VERSION 5.7 ;
  NOWIREEXTENSIONATPIN ON ;
  DIVIDERCHAR "/" ;
  BUSBITCHARS "[]" ;
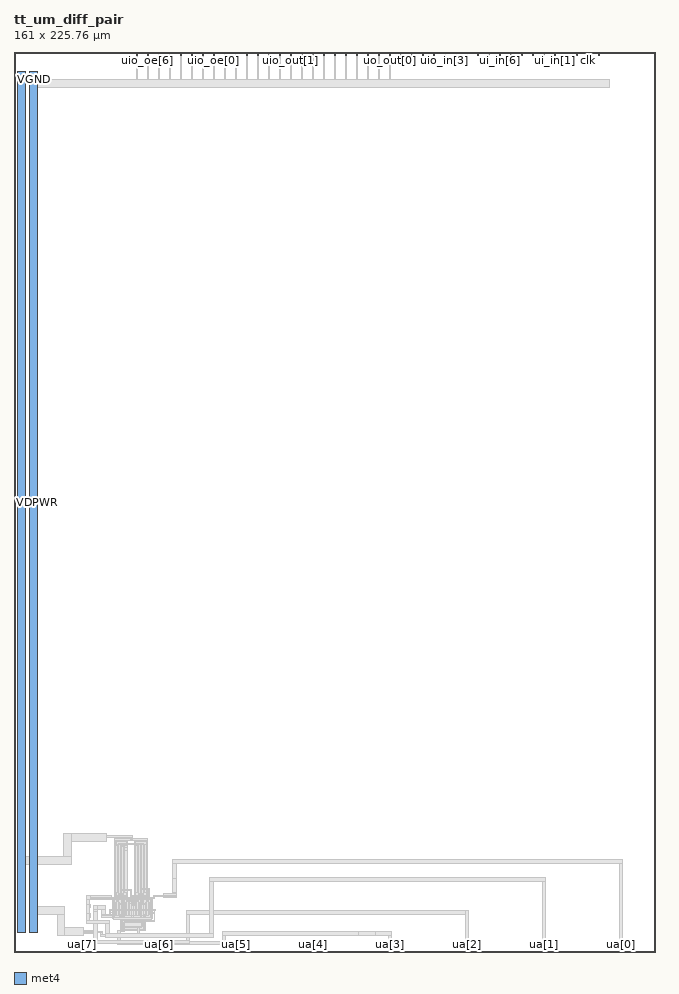
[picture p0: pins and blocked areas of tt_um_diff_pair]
MACRO tt_um_diff_pair
  CLASS BLOCK ;
  FOREIGN tt_um_diff_pair ;
  ORIGIN 0.000 0.000 ;
  SIZE 161.000 BY 225.760 ;
  PIN clk
    DIRECTION INPUT ;
    USE SIGNAL ;
    PORT
      LAYER met4 ;
        RECT 143.830 224.760 144.130 225.760 ;
    END
  END clk
  PIN ena
    DIRECTION INPUT ;
    USE SIGNAL ;
    PORT
      LAYER met4 ;
        RECT 146.590 224.760 146.890 225.760 ;
    END
  END ena
  PIN rst_n
    DIRECTION INPUT ;
    USE SIGNAL ;
    PORT
      LAYER met4 ;
        RECT 141.070 224.760 141.370 225.760 ;
    END
  END rst_n
  PIN ua[0]
    DIRECTION INOUT ;
    USE SIGNAL ;
    ANTENNADIFFAREA 5.220000 ;
    PORT
      LAYER met4 ;
        RECT 151.810 0.000 152.710 1.000 ;
    END
  END ua[0]
  PIN ua[1]
    DIRECTION INOUT ;
    USE SIGNAL ;
    ANTENNAGATEAREA 3.000000 ;
    PORT
      LAYER met4 ;
        RECT 132.490 0.000 133.390 1.000 ;
    END
  END ua[1]
  PIN ua[2]
    DIRECTION INOUT ;
    USE SIGNAL ;
    ANTENNAGATEAREA 3.000000 ;
    PORT
      LAYER met4 ;
        RECT 113.170 0.000 114.070 1.000 ;
    END
  END ua[2]
  PIN ua[3]
    DIRECTION INOUT ;
    USE SIGNAL ;
    ANTENNAGATEAREA 4.000000 ;
    PORT
      LAYER met4 ;
        RECT 93.850 0.000 94.750 1.000 ;
    END
  END ua[3]
  PIN ua[4]
    DIRECTION INOUT ;
    USE SIGNAL ;
    PORT
      LAYER met4 ;
        RECT 74.530 0.000 75.430 1.000 ;
    END
  END ua[4]
  PIN ua[5]
    DIRECTION INOUT ;
    USE SIGNAL ;
    PORT
      LAYER met4 ;
        RECT 55.210 0.000 56.110 1.000 ;
    END
  END ua[5]
  PIN ua[6]
    DIRECTION INOUT ;
    USE SIGNAL ;
    PORT
      LAYER met4 ;
        RECT 35.890 0.000 36.790 1.000 ;
    END
  END ua[6]
  PIN ua[7]
    DIRECTION INOUT ;
    USE SIGNAL ;
    PORT
      LAYER met4 ;
        RECT 16.570 0.000 17.470 1.000 ;
    END
  END ua[7]
  PIN ui_in[0]
    DIRECTION INPUT ;
    USE SIGNAL ;
    PORT
      LAYER met4 ;
        RECT 138.310 224.760 138.610 225.760 ;
    END
  END ui_in[0]
  PIN ui_in[1]
    DIRECTION INPUT ;
    USE SIGNAL ;
    PORT
      LAYER met4 ;
        RECT 135.550 224.760 135.850 225.760 ;
    END
  END ui_in[1]
  PIN ui_in[2]
    DIRECTION INPUT ;
    USE SIGNAL ;
    PORT
      LAYER met4 ;
        RECT 132.790 224.760 133.090 225.760 ;
    END
  END ui_in[2]
  PIN ui_in[3]
    DIRECTION INPUT ;
    USE SIGNAL ;
    PORT
      LAYER met4 ;
        RECT 130.030 224.760 130.330 225.760 ;
    END
  END ui_in[3]
  PIN ui_in[4]
    DIRECTION INPUT ;
    USE SIGNAL ;
    PORT
      LAYER met4 ;
        RECT 127.270 224.760 127.570 225.760 ;
    END
  END ui_in[4]
  PIN ui_in[5]
    DIRECTION INPUT ;
    USE SIGNAL ;
    PORT
      LAYER met4 ;
        RECT 124.510 224.760 124.810 225.760 ;
    END
  END ui_in[5]
  PIN ui_in[6]
    DIRECTION INPUT ;
    USE SIGNAL ;
    PORT
      LAYER met4 ;
        RECT 121.750 224.760 122.050 225.760 ;
    END
  END ui_in[6]
  PIN ui_in[7]
    DIRECTION INPUT ;
    USE SIGNAL ;
    PORT
      LAYER met4 ;
        RECT 118.990 224.760 119.290 225.760 ;
    END
  END ui_in[7]
  PIN uio_in[0]
    DIRECTION INPUT ;
    USE SIGNAL ;
    PORT
      LAYER met4 ;
        RECT 116.230 224.760 116.530 225.760 ;
    END
  END uio_in[0]
  PIN uio_in[1]
    DIRECTION INPUT ;
    USE SIGNAL ;
    PORT
      LAYER met4 ;
        RECT 113.470 224.760 113.770 225.760 ;
    END
  END uio_in[1]
  PIN uio_in[2]
    DIRECTION INPUT ;
    USE SIGNAL ;
    PORT
      LAYER met4 ;
        RECT 110.710 224.760 111.010 225.760 ;
    END
  END uio_in[2]
  PIN uio_in[3]
    DIRECTION INPUT ;
    USE SIGNAL ;
    PORT
      LAYER met4 ;
        RECT 107.950 224.760 108.250 225.760 ;
    END
  END uio_in[3]
  PIN uio_in[4]
    DIRECTION INPUT ;
    USE SIGNAL ;
    PORT
      LAYER met4 ;
        RECT 105.190 224.760 105.490 225.760 ;
    END
  END uio_in[4]
  PIN uio_in[5]
    DIRECTION INPUT ;
    USE SIGNAL ;
    PORT
      LAYER met4 ;
        RECT 102.430 224.760 102.730 225.760 ;
    END
  END uio_in[5]
  PIN uio_in[6]
    DIRECTION INPUT ;
    USE SIGNAL ;
    PORT
      LAYER met4 ;
        RECT 99.670 224.760 99.970 225.760 ;
    END
  END uio_in[6]
  PIN uio_in[7]
    DIRECTION INPUT ;
    USE SIGNAL ;
    PORT
      LAYER met4 ;
        RECT 96.910 224.760 97.210 225.760 ;
    END
  END uio_in[7]
  PIN uio_oe[0]
    DIRECTION OUTPUT ;
    USE SIGNAL ;
    ANTENNADIFFAREA 1.160000 ;
    PORT
      LAYER met4 ;
        RECT 49.990 224.760 50.290 225.760 ;
    END
  END uio_oe[0]
  PIN uio_oe[1]
    DIRECTION OUTPUT ;
    USE SIGNAL ;
    ANTENNADIFFAREA 1.160000 ;
    PORT
      LAYER met4 ;
        RECT 47.230 224.760 47.530 225.760 ;
    END
  END uio_oe[1]
  PIN uio_oe[2]
    DIRECTION OUTPUT ;
    USE SIGNAL ;
    ANTENNADIFFAREA 1.160000 ;
    PORT
      LAYER met4 ;
        RECT 44.470 224.760 44.770 225.760 ;
    END
  END uio_oe[2]
  PIN uio_oe[3]
    DIRECTION OUTPUT ;
    USE SIGNAL ;
    ANTENNADIFFAREA 1.160000 ;
    PORT
      LAYER met4 ;
        RECT 41.710 224.760 42.010 225.760 ;
    END
  END uio_oe[3]
  PIN uio_oe[4]
    DIRECTION OUTPUT ;
    USE SIGNAL ;
    ANTENNADIFFAREA 1.160000 ;
    PORT
      LAYER met4 ;
        RECT 38.950 224.760 39.250 225.760 ;
    END
  END uio_oe[4]
  PIN uio_oe[5]
    DIRECTION OUTPUT ;
    USE SIGNAL ;
    ANTENNADIFFAREA 1.160000 ;
    PORT
      LAYER met4 ;
        RECT 36.190 224.760 36.490 225.760 ;
    END
  END uio_oe[5]
  PIN uio_oe[6]
    DIRECTION OUTPUT ;
    USE SIGNAL ;
    ANTENNADIFFAREA 1.160000 ;
    PORT
      LAYER met4 ;
        RECT 33.430 224.760 33.730 225.760 ;
    END
  END uio_oe[6]
  PIN uio_oe[7]
    DIRECTION OUTPUT ;
    USE SIGNAL ;
    ANTENNADIFFAREA 1.160000 ;
    PORT
      LAYER met4 ;
        RECT 30.670 224.760 30.970 225.760 ;
    END
  END uio_oe[7]
  PIN uio_out[0]
    DIRECTION OUTPUT ;
    USE SIGNAL ;
    ANTENNADIFFAREA 1.160000 ;
    PORT
      LAYER met4 ;
        RECT 72.070 224.760 72.370 225.760 ;
    END
  END uio_out[0]
  PIN uio_out[1]
    DIRECTION OUTPUT ;
    USE SIGNAL ;
    ANTENNADIFFAREA 1.160000 ;
    PORT
      LAYER met4 ;
        RECT 69.310 224.760 69.610 225.760 ;
    END
  END uio_out[1]
  PIN uio_out[2]
    DIRECTION OUTPUT ;
    USE SIGNAL ;
    ANTENNADIFFAREA 1.160000 ;
    PORT
      LAYER met4 ;
        RECT 66.550 224.760 66.850 225.760 ;
    END
  END uio_out[2]
  PIN uio_out[3]
    DIRECTION OUTPUT ;
    USE SIGNAL ;
    ANTENNADIFFAREA 1.160000 ;
    PORT
      LAYER met4 ;
        RECT 63.790 224.760 64.090 225.760 ;
    END
  END uio_out[3]
  PIN uio_out[4]
    DIRECTION OUTPUT ;
    USE SIGNAL ;
    ANTENNADIFFAREA 1.160000 ;
    PORT
      LAYER met4 ;
        RECT 61.030 224.760 61.330 225.760 ;
    END
  END uio_out[4]
  PIN uio_out[5]
    DIRECTION OUTPUT ;
    USE SIGNAL ;
    ANTENNADIFFAREA 1.160000 ;
    PORT
      LAYER met4 ;
        RECT 58.270 224.760 58.570 225.760 ;
    END
  END uio_out[5]
  PIN uio_out[6]
    DIRECTION OUTPUT ;
    USE SIGNAL ;
    ANTENNADIFFAREA 1.160000 ;
    PORT
      LAYER met4 ;
        RECT 55.510 224.760 55.810 225.760 ;
    END
  END uio_out[6]
  PIN uio_out[7]
    DIRECTION OUTPUT ;
    USE SIGNAL ;
    ANTENNADIFFAREA 1.160000 ;
    PORT
      LAYER met4 ;
        RECT 52.750 224.760 53.050 225.760 ;
    END
  END uio_out[7]
  PIN uo_out[0]
    DIRECTION OUTPUT ;
    USE SIGNAL ;
    ANTENNADIFFAREA 1.160000 ;
    PORT
      LAYER met4 ;
        RECT 94.150 224.760 94.450 225.760 ;
    END
  END uo_out[0]
  PIN uo_out[1]
    DIRECTION OUTPUT ;
    USE SIGNAL ;
    ANTENNADIFFAREA 1.160000 ;
    PORT
      LAYER met4 ;
        RECT 91.390 224.760 91.690 225.760 ;
    END
  END uo_out[1]
  PIN uo_out[2]
    DIRECTION OUTPUT ;
    USE SIGNAL ;
    ANTENNADIFFAREA 1.160000 ;
    PORT
      LAYER met4 ;
        RECT 88.630 224.760 88.930 225.760 ;
    END
  END uo_out[2]
  PIN uo_out[3]
    DIRECTION OUTPUT ;
    USE SIGNAL ;
    ANTENNADIFFAREA 1.160000 ;
    PORT
      LAYER met4 ;
        RECT 85.870 224.760 86.170 225.760 ;
    END
  END uo_out[3]
  PIN uo_out[4]
    DIRECTION OUTPUT ;
    USE SIGNAL ;
    ANTENNADIFFAREA 1.160000 ;
    PORT
      LAYER met4 ;
        RECT 83.110 224.760 83.410 225.760 ;
    END
  END uo_out[4]
  PIN uo_out[5]
    DIRECTION OUTPUT ;
    USE SIGNAL ;
    ANTENNADIFFAREA 1.160000 ;
    PORT
      LAYER met4 ;
        RECT 80.350 224.760 80.650 225.760 ;
    END
  END uo_out[5]
  PIN uo_out[6]
    DIRECTION OUTPUT ;
    USE SIGNAL ;
    ANTENNADIFFAREA 1.160000 ;
    PORT
      LAYER met4 ;
        RECT 77.590 224.760 77.890 225.760 ;
    END
  END uo_out[6]
  PIN uo_out[7]
    DIRECTION OUTPUT ;
    USE SIGNAL ;
    ANTENNADIFFAREA 1.160000 ;
    PORT
      LAYER met4 ;
        RECT 74.830 224.760 75.130 225.760 ;
    END
  END uo_out[7]
  PIN VDPWR
    DIRECTION INOUT ;
    USE POWER ;
    PORT
      LAYER met4 ;
        RECT 1.000 5.000 3.000 220.760 ;
    END
  END VDPWR
  PIN VGND
    DIRECTION INOUT ;
    USE GROUND ;
    PORT
      LAYER met4 ;
        RECT 4.000 5.000 6.000 220.760 ;
    END
  END VGND
  OBS
      LAYER nwell ;
        RECT 25.290 13.755 28.540 27.945 ;
        RECT 30.225 13.760 33.475 27.950 ;
      LAYER pwell ;
        RECT 24.815 8.385 34.655 13.485 ;
        RECT 26.810 5.415 32.910 8.375 ;
      LAYER li1 ;
        RECT 25.270 28.090 33.500 28.520 ;
        RECT 25.640 27.765 28.250 28.090 ;
        RECT 30.540 27.770 33.150 28.090 ;
        RECT 25.470 27.595 28.360 27.765 ;
        RECT 25.470 26.820 25.640 27.595 ;
        RECT 26.270 27.085 26.770 27.255 ;
        RECT 27.060 27.085 27.560 27.255 ;
        RECT 26.040 26.820 26.210 26.870 ;
        RECT 25.470 14.870 26.210 26.820 ;
        RECT 25.470 14.105 25.640 14.870 ;
        RECT 26.040 14.830 26.210 14.870 ;
        RECT 26.830 26.620 27.000 26.870 ;
        RECT 27.200 26.620 27.430 27.085 ;
        RECT 26.830 26.370 27.430 26.620 ;
        RECT 27.620 26.795 27.790 26.870 ;
        RECT 28.190 26.795 28.360 27.595 ;
        RECT 30.405 27.600 33.295 27.770 ;
        RECT 30.405 26.835 30.575 27.600 ;
        RECT 31.205 27.090 31.705 27.260 ;
        RECT 31.995 27.090 32.495 27.260 ;
        RECT 30.975 26.835 31.145 26.875 ;
        RECT 26.830 26.360 27.330 26.370 ;
        RECT 26.830 26.100 27.000 26.360 ;
        RECT 27.620 26.100 28.365 26.795 ;
        RECT 26.830 25.450 27.020 26.100 ;
        RECT 27.600 25.450 28.365 26.100 ;
        RECT 26.830 14.830 27.000 25.450 ;
        RECT 27.620 14.845 28.365 25.450 ;
        RECT 30.405 14.885 31.180 26.835 ;
        RECT 27.620 14.830 27.790 14.845 ;
        RECT 26.270 14.445 26.770 14.615 ;
        RECT 27.060 14.445 27.560 14.615 ;
        RECT 28.190 14.105 28.360 14.845 ;
        RECT 25.470 13.935 28.360 14.105 ;
        RECT 30.405 14.110 30.575 14.885 ;
        RECT 30.975 14.835 31.145 14.885 ;
        RECT 31.765 14.835 31.935 26.875 ;
        RECT 32.555 26.870 32.725 26.875 ;
        RECT 33.125 26.870 33.295 27.600 ;
        RECT 32.555 14.920 33.325 26.870 ;
        RECT 32.555 14.835 32.725 14.920 ;
        RECT 31.205 14.450 31.705 14.620 ;
        RECT 31.995 14.450 32.495 14.620 ;
        RECT 33.125 14.110 33.295 14.920 ;
        RECT 30.405 13.940 33.295 14.110 ;
        RECT 24.995 13.135 27.095 13.305 ;
        RECT 24.995 8.735 25.165 13.135 ;
        RECT 25.795 12.625 26.295 12.795 ;
        RECT 25.565 9.415 25.735 12.455 ;
        RECT 26.355 9.415 26.525 12.455 ;
        RECT 25.795 9.075 26.295 9.245 ;
        RECT 26.925 8.735 27.095 13.135 ;
        RECT 24.995 8.670 27.095 8.735 ;
        RECT 27.455 13.135 29.555 13.305 ;
        RECT 27.455 8.735 27.625 13.135 ;
        RECT 28.255 12.625 28.755 12.795 ;
        RECT 28.025 9.415 28.195 12.455 ;
        RECT 28.815 9.415 28.985 12.455 ;
        RECT 28.255 9.075 28.755 9.245 ;
        RECT 29.385 8.735 29.555 13.135 ;
        RECT 27.455 8.670 29.555 8.735 ;
        RECT 29.915 13.135 32.015 13.305 ;
        RECT 29.915 8.735 30.085 13.135 ;
        RECT 30.715 12.625 31.215 12.795 ;
        RECT 30.485 9.415 30.655 12.455 ;
        RECT 31.275 9.415 31.445 12.455 ;
        RECT 30.715 9.075 31.215 9.245 ;
        RECT 31.845 8.735 32.015 13.135 ;
        RECT 29.915 8.670 32.015 8.735 ;
        RECT 32.375 13.135 34.475 13.305 ;
        RECT 32.375 8.735 32.545 13.135 ;
        RECT 33.175 12.625 33.675 12.795 ;
        RECT 32.945 9.415 33.115 12.455 ;
        RECT 33.735 9.415 33.905 12.455 ;
        RECT 33.175 9.075 33.675 9.245 ;
        RECT 34.305 8.735 34.475 13.135 ;
        RECT 32.375 8.670 34.475 8.735 ;
        RECT 24.980 8.565 34.475 8.670 ;
        RECT 24.980 8.060 34.470 8.565 ;
        RECT 26.990 8.025 32.730 8.060 ;
        RECT 26.990 5.765 27.160 8.025 ;
        RECT 27.840 7.455 31.880 7.625 ;
        RECT 27.500 6.395 27.670 7.395 ;
        RECT 32.050 6.395 32.220 7.395 ;
        RECT 27.840 6.165 31.880 6.335 ;
        RECT 32.560 5.765 32.730 8.025 ;
        RECT 26.990 5.595 32.730 5.765 ;
      LAYER met1 ;
        RECT 21.120 29.255 23.120 29.830 ;
        RECT 20.445 28.825 29.635 29.255 ;
        RECT 21.120 27.770 23.120 28.825 ;
        RECT 29.205 28.550 29.635 28.825 ;
        RECT 29.145 28.120 29.695 28.550 ;
        RECT 26.290 27.250 26.750 27.285 ;
        RECT 27.080 27.250 27.540 27.285 ;
        RECT 31.225 27.250 31.685 27.290 ;
        RECT 32.015 27.250 32.475 27.290 ;
        RECT 26.290 27.090 32.475 27.250 ;
        RECT 26.290 27.055 26.750 27.090 ;
        RECT 27.080 27.055 27.540 27.090 ;
        RECT 31.225 27.060 31.685 27.090 ;
        RECT 32.015 27.060 32.475 27.090 ;
        RECT 26.010 14.850 26.240 26.850 ;
        RECT 26.800 15.660 27.030 26.850 ;
        RECT 26.800 15.340 27.060 15.660 ;
        RECT 26.800 14.850 27.030 15.340 ;
        RECT 27.590 14.850 27.820 26.850 ;
        RECT 30.945 14.855 31.175 26.855 ;
        RECT 31.735 16.020 31.965 26.855 ;
        RECT 31.720 15.700 32.020 16.020 ;
        RECT 31.735 14.855 31.965 15.700 ;
        RECT 32.525 14.855 32.755 26.855 ;
        RECT 39.840 15.060 40.805 15.965 ;
        RECT 26.290 14.415 26.750 14.645 ;
        RECT 27.080 14.415 27.540 14.645 ;
        RECT 31.225 14.420 31.685 14.650 ;
        RECT 32.015 14.420 32.475 14.650 ;
        RECT 39.870 14.595 40.775 15.060 ;
        RECT 29.260 14.285 29.580 14.290 ;
        RECT 37.530 14.285 40.775 14.595 ;
        RECT 18.150 14.150 19.050 14.180 ;
        RECT 18.150 13.660 24.530 14.150 ;
        RECT 29.260 14.035 30.285 14.285 ;
        RECT 29.260 14.030 29.580 14.035 ;
        RECT 30.035 13.675 30.285 14.035 ;
        RECT 35.000 14.000 40.775 14.285 ;
        RECT 35.010 13.735 35.255 14.000 ;
        RECT 27.365 13.660 29.840 13.665 ;
        RECT 18.150 13.485 29.840 13.660 ;
        RECT 18.150 13.250 24.530 13.485 ;
        RECT 27.365 13.480 29.840 13.485 ;
        RECT 18.150 13.220 19.050 13.250 ;
        RECT 25.815 12.595 26.275 12.825 ;
        RECT 28.275 12.800 28.735 12.825 ;
        RECT 29.655 12.800 29.840 13.480 ;
        RECT 30.035 13.425 32.390 13.675 ;
        RECT 30.735 12.800 31.195 12.825 ;
        RECT 28.250 12.610 31.210 12.800 ;
        RECT 28.275 12.595 28.735 12.610 ;
        RECT 30.735 12.595 31.195 12.610 ;
        RECT 20.020 11.620 20.920 11.650 ;
        RECT 20.020 10.720 22.860 11.620 ;
        RECT 20.020 10.690 20.920 10.720 ;
        RECT 21.960 9.490 22.860 10.720 ;
        RECT 24.000 9.990 24.320 10.020 ;
        RECT 25.535 9.990 25.765 12.435 ;
        RECT 24.000 9.790 25.765 9.990 ;
        RECT 24.000 9.760 24.320 9.790 ;
        RECT 21.960 9.275 24.595 9.490 ;
        RECT 25.535 9.435 25.765 9.790 ;
        RECT 26.325 12.150 26.555 12.435 ;
        RECT 26.325 11.890 27.450 12.150 ;
        RECT 26.325 9.435 26.555 11.890 ;
        RECT 27.995 10.680 28.225 12.435 ;
        RECT 28.785 12.280 29.015 12.435 ;
        RECT 29.580 12.280 29.840 12.370 ;
        RECT 30.455 12.280 30.685 12.435 ;
        RECT 28.785 12.140 30.685 12.280 ;
        RECT 27.980 10.360 28.240 10.680 ;
        RECT 27.995 9.435 28.225 10.360 ;
        RECT 28.785 9.435 29.015 12.140 ;
        RECT 29.580 12.050 29.840 12.140 ;
        RECT 30.455 9.435 30.685 12.140 ;
        RECT 31.245 10.680 31.475 12.435 ;
        RECT 32.140 12.280 32.390 13.425 ;
        RECT 35.000 13.415 35.260 13.735 ;
        RECT 37.530 13.690 40.775 14.000 ;
        RECT 33.195 12.595 33.655 12.825 ;
        RECT 32.915 12.280 33.145 12.435 ;
        RECT 32.140 12.030 33.145 12.280 ;
        RECT 31.230 10.360 31.490 10.680 ;
        RECT 31.245 9.435 31.475 10.360 ;
        RECT 32.915 9.435 33.145 12.030 ;
        RECT 33.705 9.960 33.935 12.435 ;
        RECT 35.070 10.390 35.390 10.650 ;
        RECT 35.130 9.960 35.330 10.390 ;
        RECT 33.705 9.760 35.330 9.960 ;
        RECT 33.705 9.435 33.935 9.760 ;
        RECT 26.440 9.275 26.760 9.290 ;
        RECT 21.960 9.055 26.760 9.275 ;
        RECT 21.960 8.595 24.595 9.055 ;
        RECT 25.810 9.045 26.760 9.055 ;
        RECT 28.275 9.045 28.735 9.275 ;
        RECT 30.735 9.045 31.195 9.275 ;
        RECT 32.555 9.270 32.875 9.285 ;
        RECT 33.195 9.270 33.655 9.275 ;
        RECT 26.440 9.030 26.760 9.045 ;
        RECT 32.555 9.040 33.660 9.270 ;
        RECT 32.555 9.025 32.875 9.040 ;
        RECT 21.960 8.590 22.860 8.595 ;
        RECT 35.130 7.830 35.330 9.760 ;
        RECT 31.280 7.655 35.330 7.830 ;
        RECT 27.860 7.630 35.330 7.655 ;
        RECT 27.860 7.425 31.860 7.630 ;
        RECT 27.480 7.375 27.670 7.410 ;
        RECT 27.470 6.415 27.700 7.375 ;
        RECT 32.020 6.415 32.250 7.375 ;
        RECT 15.545 5.245 19.765 5.505 ;
        RECT 25.865 5.300 26.820 5.475 ;
        RECT 27.480 5.300 27.670 6.415 ;
        RECT 27.860 6.135 31.860 6.365 ;
        RECT 15.545 4.820 22.085 5.245 ;
        RECT 25.865 5.110 27.670 5.300 ;
        RECT 15.545 4.555 19.765 4.820 ;
        RECT 21.660 4.280 22.080 4.820 ;
        RECT 25.865 4.580 26.820 5.110 ;
        RECT 31.040 4.280 31.460 6.135 ;
        RECT 21.660 3.860 31.460 4.280 ;
      LAYER met2 ;
        RECT 12.490 29.775 23.150 29.800 ;
        RECT 12.470 27.825 23.150 29.775 ;
        RECT 12.490 27.800 23.150 27.825 ;
        RECT 39.870 19.230 40.775 19.255 ;
        RECT 39.850 18.375 40.795 19.230 ;
        RECT 31.690 15.985 32.050 15.990 ;
        RECT 31.690 15.735 34.010 15.985 ;
        RECT 31.690 15.730 32.050 15.735 ;
        RECT 26.770 15.370 29.560 15.630 ;
        RECT 29.300 14.320 29.560 15.370 ;
        RECT 18.120 13.250 19.080 14.150 ;
        RECT 29.290 14.000 29.560 14.320 ;
        RECT 29.300 13.780 29.560 14.000 ;
        RECT 27.160 13.520 29.560 13.780 ;
        RECT 33.760 13.640 34.010 15.735 ;
        RECT 39.870 15.030 40.775 18.375 ;
        RECT 34.970 13.695 35.290 13.705 ;
        RECT 34.880 13.640 35.290 13.695 ;
        RECT 18.150 11.915 19.050 13.250 ;
        RECT 18.130 11.065 19.070 11.915 ;
        RECT 27.160 11.860 27.420 13.520 ;
        RECT 30.140 13.500 35.290 13.640 ;
        RECT 29.635 12.340 29.785 12.535 ;
        RECT 30.140 12.495 30.280 13.500 ;
        RECT 33.760 13.495 34.010 13.500 ;
        RECT 34.880 13.450 35.290 13.500 ;
        RECT 34.970 13.445 35.290 13.450 ;
        RECT 29.550 12.080 29.870 12.340 ;
        RECT 29.635 11.745 29.785 12.080 ;
        RECT 30.135 11.745 30.285 12.495 ;
        RECT 18.150 11.040 19.050 11.065 ;
        RECT 19.990 10.720 20.950 11.620 ;
        RECT 29.635 11.595 30.285 11.745 ;
        RECT 20.020 10.045 20.920 10.720 ;
        RECT 27.950 10.620 28.270 10.650 ;
        RECT 31.200 10.620 31.520 10.650 ;
        RECT 35.100 10.620 35.360 10.680 ;
        RECT 24.060 10.420 35.360 10.620 ;
        RECT 24.060 10.050 24.260 10.420 ;
        RECT 27.950 10.390 28.270 10.420 ;
        RECT 31.200 10.390 31.520 10.420 ;
        RECT 35.100 10.360 35.360 10.420 ;
        RECT 20.000 9.195 20.940 10.045 ;
        RECT 24.030 9.730 24.290 10.050 ;
        RECT 26.470 9.275 26.730 9.320 ;
        RECT 26.470 9.270 28.780 9.275 ;
        RECT 32.585 9.270 32.845 9.315 ;
        RECT 20.020 9.170 20.920 9.195 ;
        RECT 26.470 9.045 32.845 9.270 ;
        RECT 26.470 9.000 26.730 9.045 ;
        RECT 32.585 8.995 32.845 9.045 ;
        RECT 10.815 6.080 12.765 6.100 ;
        RECT 10.790 4.080 17.540 6.080 ;
        RECT 10.815 4.060 12.765 4.080 ;
        RECT 25.895 2.710 26.790 5.505 ;
        RECT 86.345 5.110 87.195 5.130 ;
        RECT 52.255 4.215 87.220 5.110 ;
        RECT 52.255 2.710 53.150 4.215 ;
        RECT 69.960 4.210 87.220 4.215 ;
        RECT 86.345 4.190 87.195 4.210 ;
        RECT 25.895 1.815 53.150 2.710 ;
      LAYER met3 ;
        RECT 1.005 23.930 2.995 23.955 ;
        RECT 12.490 23.930 14.490 29.800 ;
        RECT 1.000 21.930 14.490 23.930 ;
        RECT 39.870 23.080 40.775 23.085 ;
        RECT 39.845 22.185 40.800 23.080 ;
        RECT 1.005 21.905 2.995 21.930 ;
        RECT 39.870 18.350 40.775 22.185 ;
        RECT 18.150 9.535 19.050 11.940 ;
        RECT 43.170 10.355 114.070 10.360 ;
        RECT 18.125 8.645 19.075 9.535 ;
        RECT 18.150 8.640 19.050 8.645 ;
        RECT 10.795 6.080 12.785 6.105 ;
        RECT 10.790 4.080 12.790 6.080 ;
        RECT 10.795 4.055 12.785 4.080 ;
        RECT 20.020 2.910 20.920 10.070 ;
        RECT 43.170 9.465 114.095 10.355 ;
        RECT 43.170 9.460 114.070 9.465 ;
        RECT 43.170 2.910 44.070 9.460 ;
        RECT 90.675 5.110 91.565 5.135 ;
        RECT 86.320 4.210 91.570 5.110 ;
        RECT 90.675 4.185 91.565 4.210 ;
        RECT 20.020 2.010 44.070 2.910 ;
      LAYER met4 ;
        RECT 30.670 218.890 30.970 224.760 ;
        RECT 33.430 218.890 33.730 224.760 ;
        RECT 36.190 218.890 36.490 224.760 ;
        RECT 38.950 218.890 39.250 224.760 ;
        RECT 41.710 218.890 42.010 224.760 ;
        RECT 44.470 218.890 44.770 224.760 ;
        RECT 47.230 218.890 47.530 224.760 ;
        RECT 49.990 218.890 50.290 224.760 ;
        RECT 52.750 218.890 53.050 224.760 ;
        RECT 55.510 218.890 55.810 224.760 ;
        RECT 58.270 218.890 58.570 224.760 ;
        RECT 61.030 218.890 61.330 224.760 ;
        RECT 63.790 218.890 64.090 224.760 ;
        RECT 66.550 218.890 66.850 224.760 ;
        RECT 69.310 218.890 69.610 224.760 ;
        RECT 72.070 218.890 72.370 224.760 ;
        RECT 74.830 218.890 75.130 224.760 ;
        RECT 77.590 218.890 77.890 224.760 ;
        RECT 80.350 218.890 80.650 224.760 ;
        RECT 83.110 218.890 83.410 224.760 ;
        RECT 85.870 218.890 86.170 224.760 ;
        RECT 88.630 218.890 88.930 224.760 ;
        RECT 91.390 218.890 91.690 224.760 ;
        RECT 94.150 218.890 94.450 224.760 ;
        RECT 6.000 216.890 149.410 218.890 ;
        RECT 39.870 23.080 72.265 23.085 ;
        RECT 39.870 22.180 152.710 23.080 ;
        RECT 49.120 17.770 133.390 18.670 ;
        RECT 6.000 9.390 12.790 11.390 ;
        RECT 10.790 4.080 12.790 9.390 ;
        RECT 18.150 8.000 19.050 9.540 ;
        RECT 18.150 7.100 23.950 8.000 ;
        RECT 23.050 4.540 23.950 7.100 ;
        RECT 49.120 4.540 50.020 17.770 ;
        RECT 23.050 3.640 50.020 4.540 ;
        RECT 90.670 4.210 94.750 5.110 ;
        RECT 93.850 1.000 94.750 4.210 ;
        RECT 113.170 1.000 114.070 10.360 ;
        RECT 132.490 1.000 133.390 17.770 ;
        RECT 151.810 1.000 152.710 22.180 ;
  END
END tt_um_diff_pair
END LIBRARY

